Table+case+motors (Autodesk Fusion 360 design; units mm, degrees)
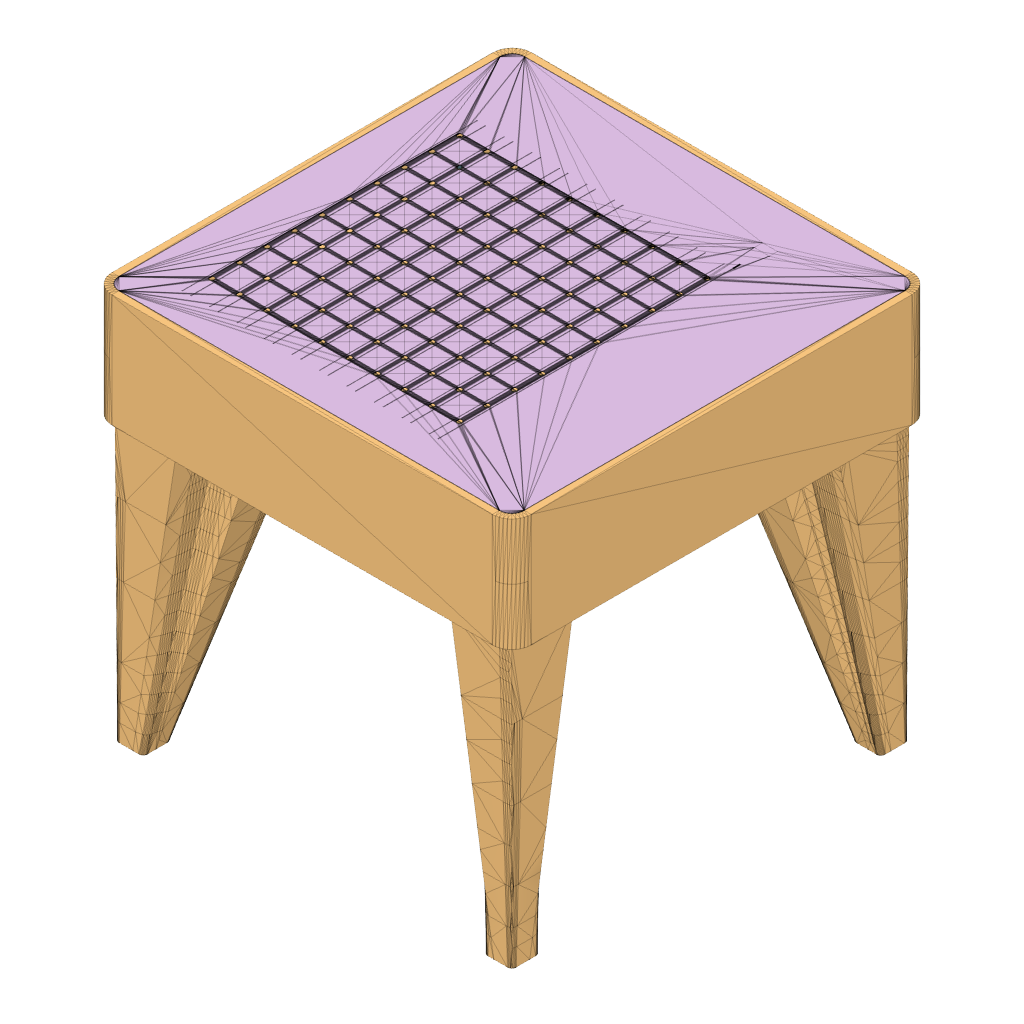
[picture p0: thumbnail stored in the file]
part number: 2026-09-26-10-21-53-032
part number: 2026-09-26-10-21-53-560
part number: 2026-09-26-10-21-53-567
part number: 2026-09-26-10-21-53-569
part number: 2026-09-26-10-21-53-571
part number: 2026-09-26-10-21-53-574
part number: 2026-09-26-10-21-53-576
part number: 2026-09-26-10-21-53-579
part number: 2026-09-26-10-21-53-581
part number: 2026-09-26-10-21-53-584
part number: 2026-09-26-10-21-53-586
part number: 2026-09-26-10-21-53-589
part number: 2026-09-26-10-21-53-591
part number: 2026-09-26-10-21-53-593
part number: 2026-09-26-10-21-53-596
part number: 2026-09-26-10-21-53-602
part number: 2026-09-26-10-21-53-604
part number: 2026-09-26-10-21-53-606
part number: 2026-09-26-10-21-53-609
part number: 2026-09-26-10-21-53-611
base_mesh_feature "Base Mesh Feature1"
base_mesh_feature "Base Mesh Feature1"
base_mesh_feature "Base Mesh Feature1"
base_mesh_feature "Base Mesh Feature1"
base_mesh_feature "Base Mesh Feature1"
base_mesh_feature "Base Mesh Feature1"
base_mesh_feature "Base Mesh Feature1"
base_mesh_feature "Base Mesh Feature1"
base_mesh_feature "Base Mesh Feature1"
base_mesh_feature "Base Mesh Feature1"
base_mesh_feature "Base Mesh Feature1"
base_mesh_feature "Base Mesh Feature1"
base_mesh_feature "Base Mesh Feature1"
base_mesh_feature "Base Mesh Feature1"
base_mesh_feature "Base Mesh Feature1"
base_mesh_feature "Base Mesh Feature1"
base_mesh_feature "Base Mesh Feature1"
base_mesh_feature "Base Mesh Feature1"
base_mesh_feature "Base Mesh Feature1"
base_mesh_feature "Base Mesh Feature1"
base_mesh_feature "Base Mesh Feature1"
base_mesh_feature "Base Mesh Feature1"
base_mesh_feature "Base Mesh Feature1"
base_mesh_feature "Base Mesh Feature1"
base_mesh_feature "Base Mesh Feature1"
base_mesh_feature "Base Mesh Feature1"
base_mesh_feature "Base Mesh Feature1"
base_mesh_feature "Base Mesh Feature1"
base_mesh_feature "Base Mesh Feature1"
base_mesh_feature "Base Mesh Feature1"
base_mesh_feature "Base Mesh Feature1"
base_mesh_feature "Base Mesh Feature1"
base_mesh_feature "Base Mesh Feature1"
base_mesh_feature "Base Mesh Feature1"
base_mesh_feature "Base Mesh Feature1"
base_mesh_feature "Base Mesh Feature1"
base_mesh_feature "Base Mesh Feature1"
base_mesh_feature "Base Mesh Feature1"
base_mesh_feature "Base Mesh Feature1"
base_mesh_feature "Base Mesh Feature1"
base_mesh_feature "Base Mesh Feature1"
base_mesh_feature "Base Mesh Feature1"
base_mesh_feature "Base Mesh Feature1"
base_mesh_feature "Base Mesh Feature1"
base_mesh_feature "Base Mesh Feature1"
base_mesh_feature "Base Mesh Feature1"
base_mesh_feature "Base Mesh Feature1"
base_mesh_feature "Base Mesh Feature1"
base_mesh_feature "Base Mesh Feature1"
base_mesh_feature "Base Mesh Feature1"
base_mesh_feature "Base Mesh Feature1"
base_mesh_feature "Base Mesh Feature1"
base_mesh_feature "Base Mesh Feature1"
base_mesh_feature "Base Mesh Feature1"
base_mesh_feature "Base Mesh Feature1"
base_mesh_feature "Base Mesh Feature1"
base_mesh_feature "Base Mesh Feature1"
base_mesh_feature "Base Mesh Feature1"
base_mesh_feature "Base Mesh Feature1"
base_mesh_feature "Base Mesh Feature1"
base_mesh_feature "Base Mesh Feature1"
base_mesh_feature "Base Mesh Feature1"
base_mesh_feature "Base Mesh Feature1"
base_mesh_feature "Base Mesh Feature1"
base_mesh_feature "Base Mesh Feature1"
base_mesh_feature "Base Mesh Feature1"
base_mesh_feature "Base Mesh Feature1"
base_mesh_feature "Base Mesh Feature1"
base_mesh_feature "Base Mesh Feature1"
base_mesh_feature "Base Mesh Feature1"
base_mesh_feature "Base Mesh Feature1"
base_mesh_feature "Base Mesh Feature1"
base_mesh_feature "Base Mesh Feature1"
base_mesh_feature "Base Mesh Feature1"
base_mesh_feature "Base Mesh Feature1"
base_mesh_feature "Base Mesh Feature1"
base_mesh_feature "Base Mesh Feature1"
base_mesh_feature "Base Mesh Feature1"
base_mesh_feature "Base Mesh Feature1"
base_mesh_feature "Base Mesh Feature1"
base_mesh_feature "Base Mesh Feature1"
base_mesh_feature "Base Mesh Feature1"
base_mesh_feature "Base Mesh Feature1"
base_mesh_feature "Base Mesh Feature1"
base_mesh_feature "Base Mesh Feature1"
base_mesh_feature "Base Mesh Feature1"
base_mesh_feature "Base Mesh Feature1"
base_mesh_feature "Base Mesh Feature1"
base_mesh_feature "Base Mesh Feature1"
base_mesh_feature "Base Mesh Feature1"
base_mesh_feature "Base Mesh Feature1"
base_mesh_feature "Base Mesh Feature1"
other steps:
create_component "CreateComponent1"
create_component "CreateComponent1"
create_component "CreateComponent2"
create_component "CreateComponent3"
create_component "CreateComponent4"
create_component "CreateComponent5"
create_component "CreateComponent6"
create_component "CreateComponent7"
create_component "CreateComponent8"
create_component "CreateComponent9"
create_component "CreateComponent10"
create_component "CreateComponent11"
create_component "CreateComponent12"
create_component "CreateComponent13"
create_component "CreateComponent14"
create_component "CreateComponent15"
create_component "CreateComponent16"
create_component "CreateComponent17"
create_component "CreateComponent18"
create_component "CreateComponent19"
create_component "CreateComponent20"
create_component "CreateComponent21"
create_component "CreateComponent22"
create_component "CreateComponent23"
create_component "CreateComponent24"
create_component "CreateComponent25"
create_component "CreateComponent26"
create_component "CreateComponent27"
create_component "CreateComponent28"
create_component "CreateComponent29"
create_component "CreateComponent30"
create_component "CreateComponent31"
create_component "CreateComponent32"
create_component "CreateComponent33"
create_component "CreateComponent34"
create_component "CreateComponent35"
create_component "CreateComponent36"
create_component "CreateComponent37"
create_component "CreateComponent38"
create_component "CreateComponent39"
create_component "CreateComponent40"
create_component "CreateComponent41"
create_component "CreateComponent42"
create_component "CreateComponent43"
create_component "CreateComponent44"
create_component "CreateComponent45"
create_component "CreateComponent46"
create_component "CreateComponent47"
create_component "CreateComponent48"
create_component "CreateComponent49"
create_component "CreateComponent50"
create_component "CreateComponent51"
create_component "CreateComponent52"
create_component "CreateComponent53"
create_component "CreateComponent54"
create_component "CreateComponent55"
create_component "CreateComponent56"
create_component "CreateComponent57"
create_component "CreateComponent58"
create_component "CreateComponent59"
create_component "CreateComponent60"
create_component "CreateComponent61"
create_component "CreateComponent62"
create_component "CreateComponent63"
create_component "CreateComponent64"
create_component "CreateComponent65"
create_component "CreateComponent66"
create_component "CreateComponent67"
create_component "CreateComponent68"
create_component "CreateComponent69"
create_component "CreateComponent70"
create_component "CreateComponent71"
create_component "CreateComponent72"
create_component "CreateComponent73"
create_component "CreateComponent74"
create_component "CreateComponent75"
create_component "CreateComponent76"
create_component "CreateComponent77"
create_component "CreateComponent78"
create_component "CreateComponent79"
create_component "CreateComponent80"
create_component "CreateComponent81"
create_component "CreateComponent82"
create_component "CreateComponent83"
create_component "CreateComponent84"
create_component "CreateComponent85"
create_component "CreateComponent86"
create_component "CreateComponent87"
create_component "CreateComponent88"
create_component "CreateComponent89"
create_component "CreateComponent90"
create_component "CreateComponent91"
create_component "CreateComponent92"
